VERSION 5.7 ;
  NOWIREEXTENSIONATPIN ON ;
  DIVIDERCHAR "/" ;
  BUSBITCHARS "[]" ;
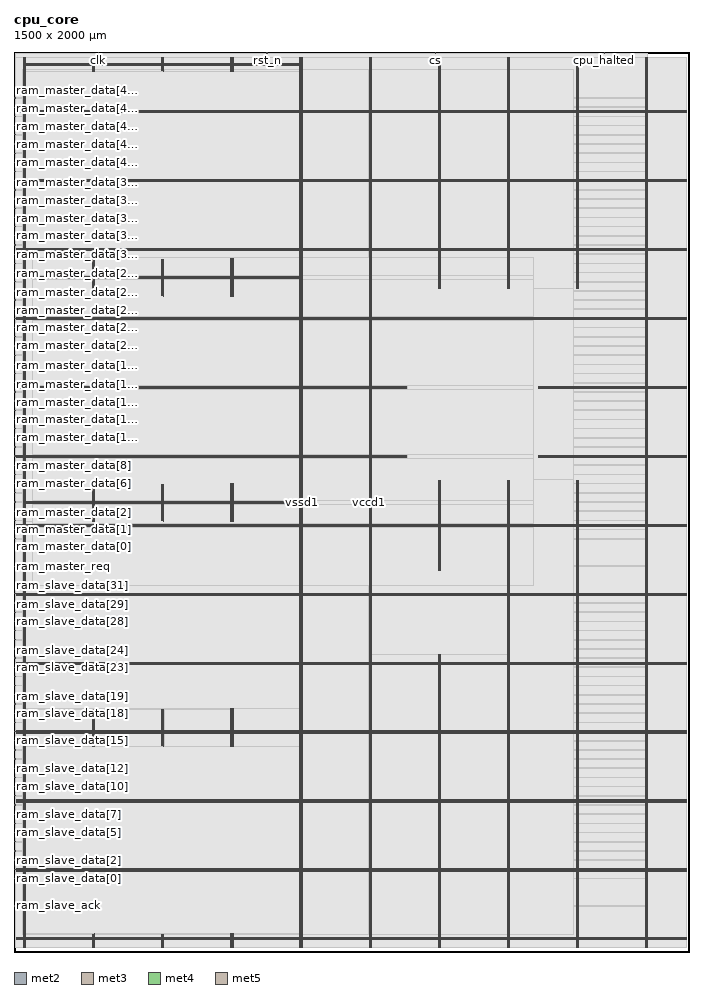
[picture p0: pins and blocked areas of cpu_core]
MACRO cpu_core
  CLASS BLOCK ;
  FOREIGN cpu_core ;
  ORIGIN 0.000 0.000 ;
  SIZE 1500.000 BY 2000.000 ;
  PIN clk
    DIRECTION INPUT ;
    USE SIGNAL ;
    ANTENNAGATEAREA 2.573400 ;
    ANTENNADIFFAREA 0.869400 ;
    PORT
      LAYER met2 ;
        RECT 187.310 1996.000 187.590 2000.000 ;
    END
  END clk
  PIN cpu_halted
    DIRECTION OUTPUT ;
    USE SIGNAL ;
    ANTENNADIFFAREA 0.445500 ;
    PORT
      LAYER met2 ;
        RECT 1312.010 1996.000 1312.290 2000.000 ;
    END
  END cpu_halted
  PIN cs
    DIRECTION INPUT ;
    USE SIGNAL ;
    ANTENNAGATEAREA 0.860700 ;
    ANTENNADIFFAREA 0.434700 ;
    PORT
      LAYER met2 ;
        RECT 937.110 1996.000 937.390 2000.000 ;
    END
  END cs
  PIN ram_master_data[0]
    DIRECTION OUTPUT ;
    USE SIGNAL ;
    ANTENNADIFFAREA 0.445500 ;
    PORT
      LAYER met3 ;
        RECT 0.000 918.040 4.000 918.640 ;
    END
  END ram_master_data[0]
  PIN ram_master_data[10]
    DIRECTION OUTPUT ;
    USE SIGNAL ;
    ANTENNADIFFAREA 0.445500 ;
    PORT
      LAYER met3 ;
        RECT 0.000 1122.040 4.000 1122.640 ;
    END
  END ram_master_data[10]
  PIN ram_master_data[11]
    DIRECTION OUTPUT ;
    USE SIGNAL ;
    ANTENNADIFFAREA 0.445500 ;
    PORT
      LAYER met3 ;
        RECT 0.000 1142.440 4.000 1143.040 ;
    END
  END ram_master_data[11]
  PIN ram_master_data[12]
    DIRECTION OUTPUT ;
    USE SIGNAL ;
    ANTENNADIFFAREA 0.445500 ;
    PORT
      LAYER met3 ;
        RECT 0.000 1162.840 4.000 1163.440 ;
    END
  END ram_master_data[12]
  PIN ram_master_data[13]
    DIRECTION OUTPUT ;
    USE SIGNAL ;
    ANTENNADIFFAREA 0.445500 ;
    PORT
      LAYER met3 ;
        RECT 0.000 1183.240 4.000 1183.840 ;
    END
  END ram_master_data[13]
  PIN ram_master_data[14]
    DIRECTION OUTPUT ;
    USE SIGNAL ;
    ANTENNADIFFAREA 0.445500 ;
    PORT
      LAYER met3 ;
        RECT 0.000 1203.640 4.000 1204.240 ;
    END
  END ram_master_data[14]
  PIN ram_master_data[15]
    DIRECTION OUTPUT ;
    USE SIGNAL ;
    ANTENNADIFFAREA 0.445500 ;
    PORT
      LAYER met3 ;
        RECT 0.000 1224.040 4.000 1224.640 ;
    END
  END ram_master_data[15]
  PIN ram_master_data[16]
    DIRECTION OUTPUT ;
    USE SIGNAL ;
    ANTENNADIFFAREA 0.445500 ;
    PORT
      LAYER met3 ;
        RECT 0.000 1244.440 4.000 1245.040 ;
    END
  END ram_master_data[16]
  PIN ram_master_data[17]
    DIRECTION OUTPUT ;
    USE SIGNAL ;
    ANTENNADIFFAREA 0.445500 ;
    PORT
      LAYER met3 ;
        RECT 0.000 1264.840 4.000 1265.440 ;
    END
  END ram_master_data[17]
  PIN ram_master_data[18]
    DIRECTION OUTPUT ;
    USE SIGNAL ;
    ANTENNADIFFAREA 0.445500 ;
    PORT
      LAYER met3 ;
        RECT 0.000 1285.240 4.000 1285.840 ;
    END
  END ram_master_data[18]
  PIN ram_master_data[19]
    DIRECTION OUTPUT ;
    USE SIGNAL ;
    ANTENNADIFFAREA 0.445500 ;
    PORT
      LAYER met3 ;
        RECT 0.000 1305.640 4.000 1306.240 ;
    END
  END ram_master_data[19]
  PIN ram_master_data[1]
    DIRECTION OUTPUT ;
    USE SIGNAL ;
    ANTENNADIFFAREA 0.445500 ;
    PORT
      LAYER met3 ;
        RECT 0.000 938.440 4.000 939.040 ;
    END
  END ram_master_data[1]
  PIN ram_master_data[20]
    DIRECTION OUTPUT ;
    USE SIGNAL ;
    ANTENNADIFFAREA 0.445500 ;
    PORT
      LAYER met3 ;
        RECT 0.000 1326.040 4.000 1326.640 ;
    END
  END ram_master_data[20]
  PIN ram_master_data[21]
    DIRECTION OUTPUT ;
    USE SIGNAL ;
    ANTENNADIFFAREA 0.445500 ;
    PORT
      LAYER met3 ;
        RECT 0.000 1346.440 4.000 1347.040 ;
    END
  END ram_master_data[21]
  PIN ram_master_data[22]
    DIRECTION OUTPUT ;
    USE SIGNAL ;
    ANTENNADIFFAREA 0.445500 ;
    PORT
      LAYER met3 ;
        RECT 0.000 1366.840 4.000 1367.440 ;
    END
  END ram_master_data[22]
  PIN ram_master_data[23]
    DIRECTION OUTPUT ;
    USE SIGNAL ;
    ANTENNADIFFAREA 0.445500 ;
    PORT
      LAYER met3 ;
        RECT 0.000 1387.240 4.000 1387.840 ;
    END
  END ram_master_data[23]
  PIN ram_master_data[24]
    DIRECTION OUTPUT ;
    USE SIGNAL ;
    ANTENNADIFFAREA 0.445500 ;
    PORT
      LAYER met3 ;
        RECT 0.000 1407.640 4.000 1408.240 ;
    END
  END ram_master_data[24]
  PIN ram_master_data[25]
    DIRECTION OUTPUT ;
    USE SIGNAL ;
    ANTENNADIFFAREA 0.445500 ;
    PORT
      LAYER met3 ;
        RECT 0.000 1428.040 4.000 1428.640 ;
    END
  END ram_master_data[25]
  PIN ram_master_data[26]
    DIRECTION OUTPUT ;
    USE SIGNAL ;
    ANTENNADIFFAREA 0.445500 ;
    PORT
      LAYER met3 ;
        RECT 0.000 1448.440 4.000 1449.040 ;
    END
  END ram_master_data[26]
  PIN ram_master_data[27]
    DIRECTION OUTPUT ;
    USE SIGNAL ;
    ANTENNADIFFAREA 0.445500 ;
    PORT
      LAYER met3 ;
        RECT 0.000 1468.840 4.000 1469.440 ;
    END
  END ram_master_data[27]
  PIN ram_master_data[28]
    DIRECTION OUTPUT ;
    USE SIGNAL ;
    ANTENNADIFFAREA 0.445500 ;
    PORT
      LAYER met3 ;
        RECT 0.000 1489.240 4.000 1489.840 ;
    END
  END ram_master_data[28]
  PIN ram_master_data[29]
    DIRECTION OUTPUT ;
    USE SIGNAL ;
    ANTENNADIFFAREA 0.445500 ;
    PORT
      LAYER met3 ;
        RECT 0.000 1509.640 4.000 1510.240 ;
    END
  END ram_master_data[29]
  PIN ram_master_data[2]
    DIRECTION OUTPUT ;
    USE SIGNAL ;
    ANTENNADIFFAREA 0.445500 ;
    PORT
      LAYER met3 ;
        RECT 0.000 958.840 4.000 959.440 ;
    END
  END ram_master_data[2]
  PIN ram_master_data[30]
    DIRECTION OUTPUT ;
    USE SIGNAL ;
    ANTENNADIFFAREA 0.445500 ;
    PORT
      LAYER met3 ;
        RECT 0.000 1530.040 4.000 1530.640 ;
    END
  END ram_master_data[30]
  PIN ram_master_data[31]
    DIRECTION OUTPUT ;
    USE SIGNAL ;
    ANTENNADIFFAREA 0.445500 ;
    PORT
      LAYER met3 ;
        RECT 0.000 1550.440 4.000 1551.040 ;
    END
  END ram_master_data[31]
  PIN ram_master_data[32]
    DIRECTION OUTPUT ;
    USE SIGNAL ;
    ANTENNADIFFAREA 0.445500 ;
    PORT
      LAYER met3 ;
        RECT 0.000 1570.840 4.000 1571.440 ;
    END
  END ram_master_data[32]
  PIN ram_master_data[33]
    DIRECTION OUTPUT ;
    USE SIGNAL ;
    ANTENNADIFFAREA 0.445500 ;
    PORT
      LAYER met3 ;
        RECT 0.000 1591.240 4.000 1591.840 ;
    END
  END ram_master_data[33]
  PIN ram_master_data[34]
    DIRECTION OUTPUT ;
    USE SIGNAL ;
    ANTENNADIFFAREA 0.445500 ;
    PORT
      LAYER met3 ;
        RECT 0.000 1611.640 4.000 1612.240 ;
    END
  END ram_master_data[34]
  PIN ram_master_data[35]
    DIRECTION OUTPUT ;
    USE SIGNAL ;
    ANTENNADIFFAREA 0.445500 ;
    PORT
      LAYER met3 ;
        RECT 0.000 1632.040 4.000 1632.640 ;
    END
  END ram_master_data[35]
  PIN ram_master_data[36]
    DIRECTION OUTPUT ;
    USE SIGNAL ;
    ANTENNADIFFAREA 0.445500 ;
    PORT
      LAYER met3 ;
        RECT 0.000 1652.440 4.000 1653.040 ;
    END
  END ram_master_data[36]
  PIN ram_master_data[37]
    DIRECTION OUTPUT ;
    USE SIGNAL ;
    ANTENNADIFFAREA 0.445500 ;
    PORT
      LAYER met3 ;
        RECT 0.000 1672.840 4.000 1673.440 ;
    END
  END ram_master_data[37]
  PIN ram_master_data[38]
    DIRECTION OUTPUT ;
    USE SIGNAL ;
    ANTENNADIFFAREA 0.445500 ;
    PORT
      LAYER met3 ;
        RECT 0.000 1693.240 4.000 1693.840 ;
    END
  END ram_master_data[38]
  PIN ram_master_data[39]
    DIRECTION OUTPUT ;
    USE SIGNAL ;
    ANTENNADIFFAREA 0.445500 ;
    PORT
      LAYER met3 ;
        RECT 0.000 1713.640 4.000 1714.240 ;
    END
  END ram_master_data[39]
  PIN ram_master_data[3]
    DIRECTION OUTPUT ;
    USE SIGNAL ;
    ANTENNADIFFAREA 0.445500 ;
    PORT
      LAYER met3 ;
        RECT 0.000 979.240 4.000 979.840 ;
    END
  END ram_master_data[3]
  PIN ram_master_data[40]
    DIRECTION OUTPUT ;
    USE SIGNAL ;
    ANTENNADIFFAREA 0.445500 ;
    PORT
      LAYER met3 ;
        RECT 0.000 1734.040 4.000 1734.640 ;
    END
  END ram_master_data[40]
  PIN ram_master_data[41]
    DIRECTION OUTPUT ;
    USE SIGNAL ;
    ANTENNADIFFAREA 0.445500 ;
    PORT
      LAYER met3 ;
        RECT 0.000 1754.440 4.000 1755.040 ;
    END
  END ram_master_data[41]
  PIN ram_master_data[42]
    DIRECTION OUTPUT ;
    USE SIGNAL ;
    ANTENNADIFFAREA 0.445500 ;
    PORT
      LAYER met3 ;
        RECT 0.000 1774.840 4.000 1775.440 ;
    END
  END ram_master_data[42]
  PIN ram_master_data[43]
    DIRECTION OUTPUT ;
    USE SIGNAL ;
    ANTENNADIFFAREA 0.445500 ;
    PORT
      LAYER met3 ;
        RECT 0.000 1795.240 4.000 1795.840 ;
    END
  END ram_master_data[43]
  PIN ram_master_data[44]
    DIRECTION OUTPUT ;
    USE SIGNAL ;
    ANTENNADIFFAREA 0.445500 ;
    PORT
      LAYER met3 ;
        RECT 0.000 1815.640 4.000 1816.240 ;
    END
  END ram_master_data[44]
  PIN ram_master_data[45]
    DIRECTION OUTPUT ;
    USE SIGNAL ;
    ANTENNADIFFAREA 0.445500 ;
    PORT
      LAYER met3 ;
        RECT 0.000 1836.040 4.000 1836.640 ;
    END
  END ram_master_data[45]
  PIN ram_master_data[46]
    DIRECTION OUTPUT ;
    USE SIGNAL ;
    ANTENNADIFFAREA 0.445500 ;
    PORT
      LAYER met3 ;
        RECT 0.000 1856.440 4.000 1857.040 ;
    END
  END ram_master_data[46]
  PIN ram_master_data[47]
    DIRECTION OUTPUT ;
    USE SIGNAL ;
    ANTENNADIFFAREA 0.445500 ;
    PORT
      LAYER met3 ;
        RECT 0.000 1876.840 4.000 1877.440 ;
    END
  END ram_master_data[47]
  PIN ram_master_data[48]
    DIRECTION OUTPUT ;
    USE SIGNAL ;
    ANTENNADIFFAREA 0.445500 ;
    PORT
      LAYER met3 ;
        RECT 0.000 1897.240 4.000 1897.840 ;
    END
  END ram_master_data[48]
  PIN ram_master_data[4]
    DIRECTION OUTPUT ;
    USE SIGNAL ;
    ANTENNADIFFAREA 0.445500 ;
    PORT
      LAYER met3 ;
        RECT 0.000 999.640 4.000 1000.240 ;
    END
  END ram_master_data[4]
  PIN ram_master_data[5]
    DIRECTION OUTPUT ;
    USE SIGNAL ;
    ANTENNADIFFAREA 0.445500 ;
    PORT
      LAYER met3 ;
        RECT 0.000 1020.040 4.000 1020.640 ;
    END
  END ram_master_data[5]
  PIN ram_master_data[6]
    DIRECTION OUTPUT ;
    USE SIGNAL ;
    ANTENNADIFFAREA 0.445500 ;
    PORT
      LAYER met3 ;
        RECT 0.000 1040.440 4.000 1041.040 ;
    END
  END ram_master_data[6]
  PIN ram_master_data[7]
    DIRECTION OUTPUT ;
    USE SIGNAL ;
    ANTENNADIFFAREA 0.445500 ;
    PORT
      LAYER met3 ;
        RECT 0.000 1060.840 4.000 1061.440 ;
    END
  END ram_master_data[7]
  PIN ram_master_data[8]
    DIRECTION OUTPUT ;
    USE SIGNAL ;
    ANTENNADIFFAREA 0.445500 ;
    PORT
      LAYER met3 ;
        RECT 0.000 1081.240 4.000 1081.840 ;
    END
  END ram_master_data[8]
  PIN ram_master_data[9]
    DIRECTION OUTPUT ;
    USE SIGNAL ;
    ANTENNADIFFAREA 0.445500 ;
    PORT
      LAYER met3 ;
        RECT 0.000 1101.640 4.000 1102.240 ;
    END
  END ram_master_data[9]
  PIN ram_master_req
    DIRECTION OUTPUT ;
    USE SIGNAL ;
    ANTENNADIFFAREA 0.445500 ;
    PORT
      LAYER met3 ;
        RECT 0.000 856.840 4.000 857.440 ;
    END
  END ram_master_req
  PIN ram_slave_ack
    DIRECTION INPUT ;
    USE SIGNAL ;
    ANTENNAGATEAREA 0.682200 ;
    ANTENNADIFFAREA 0.434700 ;
    PORT
      LAYER met3 ;
        RECT 0.000 102.040 4.000 102.640 ;
    END
  END ram_slave_ack
  PIN ram_slave_data[0]
    DIRECTION INPUT ;
    USE SIGNAL ;
    ANTENNAGATEAREA 0.593700 ;
    ANTENNADIFFAREA 0.434700 ;
    PORT
      LAYER met3 ;
        RECT 0.000 163.240 4.000 163.840 ;
    END
  END ram_slave_data[0]
  PIN ram_slave_data[10]
    DIRECTION INPUT ;
    USE SIGNAL ;
    ANTENNAGATEAREA 0.631200 ;
    ANTENNADIFFAREA 0.434700 ;
    PORT
      LAYER met3 ;
        RECT 0.000 367.240 4.000 367.840 ;
    END
  END ram_slave_data[10]
  PIN ram_slave_data[11]
    DIRECTION INPUT ;
    USE SIGNAL ;
    ANTENNAGATEAREA 0.631200 ;
    ANTENNADIFFAREA 0.434700 ;
    PORT
      LAYER met3 ;
        RECT 0.000 387.640 4.000 388.240 ;
    END
  END ram_slave_data[11]
  PIN ram_slave_data[12]
    DIRECTION INPUT ;
    USE SIGNAL ;
    ANTENNAGATEAREA 0.631200 ;
    ANTENNADIFFAREA 0.434700 ;
    PORT
      LAYER met3 ;
        RECT 0.000 408.040 4.000 408.640 ;
    END
  END ram_slave_data[12]
  PIN ram_slave_data[13]
    DIRECTION INPUT ;
    USE SIGNAL ;
    ANTENNAGATEAREA 0.631200 ;
    ANTENNADIFFAREA 0.434700 ;
    PORT
      LAYER met3 ;
        RECT 0.000 428.440 4.000 429.040 ;
    END
  END ram_slave_data[13]
  PIN ram_slave_data[14]
    DIRECTION INPUT ;
    USE SIGNAL ;
    ANTENNAGATEAREA 0.631200 ;
    ANTENNADIFFAREA 0.434700 ;
    PORT
      LAYER met3 ;
        RECT 0.000 448.840 4.000 449.440 ;
    END
  END ram_slave_data[14]
  PIN ram_slave_data[15]
    DIRECTION INPUT ;
    USE SIGNAL ;
    ANTENNAGATEAREA 0.631200 ;
    ANTENNADIFFAREA 0.434700 ;
    PORT
      LAYER met3 ;
        RECT 0.000 469.240 4.000 469.840 ;
    END
  END ram_slave_data[15]
  PIN ram_slave_data[16]
    DIRECTION INPUT ;
    USE SIGNAL ;
    ANTENNAGATEAREA 0.631200 ;
    ANTENNADIFFAREA 0.434700 ;
    PORT
      LAYER met3 ;
        RECT 0.000 489.640 4.000 490.240 ;
    END
  END ram_slave_data[16]
  PIN ram_slave_data[17]
    DIRECTION INPUT ;
    USE SIGNAL ;
    ANTENNAGATEAREA 0.631200 ;
    ANTENNADIFFAREA 0.434700 ;
    PORT
      LAYER met3 ;
        RECT 0.000 510.040 4.000 510.640 ;
    END
  END ram_slave_data[17]
  PIN ram_slave_data[18]
    DIRECTION INPUT ;
    USE SIGNAL ;
    ANTENNAGATEAREA 0.631200 ;
    ANTENNADIFFAREA 0.434700 ;
    PORT
      LAYER met3 ;
        RECT 0.000 530.440 4.000 531.040 ;
    END
  END ram_slave_data[18]
  PIN ram_slave_data[19]
    DIRECTION INPUT ;
    USE SIGNAL ;
    ANTENNAGATEAREA 0.631200 ;
    ANTENNADIFFAREA 0.434700 ;
    PORT
      LAYER met3 ;
        RECT 0.000 550.840 4.000 551.440 ;
    END
  END ram_slave_data[19]
  PIN ram_slave_data[1]
    DIRECTION INPUT ;
    USE SIGNAL ;
    ANTENNAGATEAREA 0.593700 ;
    ANTENNADIFFAREA 0.434700 ;
    PORT
      LAYER met3 ;
        RECT 0.000 183.640 4.000 184.240 ;
    END
  END ram_slave_data[1]
  PIN ram_slave_data[20]
    DIRECTION INPUT ;
    USE SIGNAL ;
    ANTENNAGATEAREA 0.631200 ;
    ANTENNADIFFAREA 0.434700 ;
    PORT
      LAYER met3 ;
        RECT 0.000 571.240 4.000 571.840 ;
    END
  END ram_slave_data[20]
  PIN ram_slave_data[21]
    DIRECTION INPUT ;
    USE SIGNAL ;
    ANTENNAGATEAREA 0.631200 ;
    ANTENNADIFFAREA 0.434700 ;
    PORT
      LAYER met3 ;
        RECT 0.000 591.640 4.000 592.240 ;
    END
  END ram_slave_data[21]
  PIN ram_slave_data[22]
    DIRECTION INPUT ;
    USE SIGNAL ;
    ANTENNAGATEAREA 0.631200 ;
    ANTENNADIFFAREA 0.434700 ;
    PORT
      LAYER met3 ;
        RECT 0.000 612.040 4.000 612.640 ;
    END
  END ram_slave_data[22]
  PIN ram_slave_data[23]
    DIRECTION INPUT ;
    USE SIGNAL ;
    ANTENNAGATEAREA 0.647700 ;
    ANTENNADIFFAREA 0.434700 ;
    PORT
      LAYER met3 ;
        RECT 0.000 632.440 4.000 633.040 ;
    END
  END ram_slave_data[23]
  PIN ram_slave_data[24]
    DIRECTION INPUT ;
    USE SIGNAL ;
    ANTENNAGATEAREA 0.647700 ;
    ANTENNADIFFAREA 0.434700 ;
    PORT
      LAYER met3 ;
        RECT 0.000 652.840 4.000 653.440 ;
    END
  END ram_slave_data[24]
  PIN ram_slave_data[25]
    DIRECTION INPUT ;
    USE SIGNAL ;
    ANTENNAGATEAREA 0.647700 ;
    ANTENNADIFFAREA 0.434700 ;
    PORT
      LAYER met3 ;
        RECT 0.000 673.240 4.000 673.840 ;
    END
  END ram_slave_data[25]
  PIN ram_slave_data[26]
    DIRECTION INPUT ;
    USE SIGNAL ;
    ANTENNAGATEAREA 0.647700 ;
    ANTENNADIFFAREA 0.434700 ;
    PORT
      LAYER met3 ;
        RECT 0.000 693.640 4.000 694.240 ;
    END
  END ram_slave_data[26]
  PIN ram_slave_data[27]
    DIRECTION INPUT ;
    USE SIGNAL ;
    ANTENNAGATEAREA 0.560700 ;
    ANTENNADIFFAREA 0.434700 ;
    PORT
      LAYER met3 ;
        RECT 0.000 714.040 4.000 714.640 ;
    END
  END ram_slave_data[27]
  PIN ram_slave_data[28]
    DIRECTION INPUT ;
    USE SIGNAL ;
    ANTENNAGATEAREA 0.560700 ;
    ANTENNADIFFAREA 0.434700 ;
    PORT
      LAYER met3 ;
        RECT 0.000 734.440 4.000 735.040 ;
    END
  END ram_slave_data[28]
  PIN ram_slave_data[29]
    DIRECTION INPUT ;
    USE SIGNAL ;
    ANTENNAGATEAREA 0.631200 ;
    ANTENNADIFFAREA 0.434700 ;
    PORT
      LAYER met3 ;
        RECT 0.000 754.840 4.000 755.440 ;
    END
  END ram_slave_data[29]
  PIN ram_slave_data[2]
    DIRECTION INPUT ;
    USE SIGNAL ;
    ANTENNAGATEAREA 0.647700 ;
    ANTENNADIFFAREA 0.434700 ;
    PORT
      LAYER met3 ;
        RECT 0.000 204.040 4.000 204.640 ;
    END
  END ram_slave_data[2]
  PIN ram_slave_data[30]
    DIRECTION INPUT ;
    USE SIGNAL ;
    ANTENNAGATEAREA 0.631200 ;
    ANTENNADIFFAREA 0.434700 ;
    PORT
      LAYER met3 ;
        RECT 0.000 775.240 4.000 775.840 ;
    END
  END ram_slave_data[30]
  PIN ram_slave_data[31]
    DIRECTION INPUT ;
    USE SIGNAL ;
    ANTENNAGATEAREA 0.631200 ;
    ANTENNADIFFAREA 0.434700 ;
    PORT
      LAYER met3 ;
        RECT 0.000 795.640 4.000 796.240 ;
    END
  END ram_slave_data[31]
  PIN ram_slave_data[3]
    DIRECTION INPUT ;
    USE SIGNAL ;
    ANTENNAGATEAREA 0.593700 ;
    ANTENNADIFFAREA 0.434700 ;
    PORT
      LAYER met3 ;
        RECT 0.000 224.440 4.000 225.040 ;
    END
  END ram_slave_data[3]
  PIN ram_slave_data[4]
    DIRECTION INPUT ;
    USE SIGNAL ;
    ANTENNAGATEAREA 0.647700 ;
    ANTENNADIFFAREA 0.434700 ;
    PORT
      LAYER met3 ;
        RECT 0.000 244.840 4.000 245.440 ;
    END
  END ram_slave_data[4]
  PIN ram_slave_data[5]
    DIRECTION INPUT ;
    USE SIGNAL ;
    ANTENNAGATEAREA 0.647700 ;
    ANTENNADIFFAREA 0.434700 ;
    PORT
      LAYER met3 ;
        RECT 0.000 265.240 4.000 265.840 ;
    END
  END ram_slave_data[5]
  PIN ram_slave_data[6]
    DIRECTION INPUT ;
    USE SIGNAL ;
    ANTENNAGATEAREA 0.647700 ;
    ANTENNADIFFAREA 0.434700 ;
    PORT
      LAYER met3 ;
        RECT 0.000 285.640 4.000 286.240 ;
    END
  END ram_slave_data[6]
  PIN ram_slave_data[7]
    DIRECTION INPUT ;
    USE SIGNAL ;
    ANTENNAGATEAREA 0.647700 ;
    ANTENNADIFFAREA 0.434700 ;
    PORT
      LAYER met3 ;
        RECT 0.000 306.040 4.000 306.640 ;
    END
  END ram_slave_data[7]
  PIN ram_slave_data[8]
    DIRECTION INPUT ;
    USE SIGNAL ;
    ANTENNAGATEAREA 0.560700 ;
    ANTENNADIFFAREA 0.434700 ;
    PORT
      LAYER met3 ;
        RECT 0.000 326.440 4.000 327.040 ;
    END
  END ram_slave_data[8]
  PIN ram_slave_data[9]
    DIRECTION INPUT ;
    USE SIGNAL ;
    ANTENNAGATEAREA 0.560700 ;
    ANTENNADIFFAREA 0.434700 ;
    PORT
      LAYER met3 ;
        RECT 0.000 346.840 4.000 347.440 ;
    END
  END ram_slave_data[9]
  PIN rst_n
    DIRECTION INPUT ;
    USE SIGNAL ;
    ANTENNAGATEAREA 0.647700 ;
    ANTENNADIFFAREA 0.434700 ;
    PORT
      LAYER met2 ;
        RECT 562.210 1996.000 562.490 2000.000 ;
    END
  END rst_n
  PIN vccd1
    DIRECTION INOUT ;
    USE POWER ;
    PORT
      LAYER met4 ;
        RECT 21.040 10.640 22.640 1988.560 ;
    END
    PORT
      LAYER met4 ;
        RECT 174.640 10.640 176.240 39.400 ;
    END
    PORT
      LAYER met4 ;
        RECT 174.640 457.180 176.240 539.400 ;
    END
    PORT
      LAYER met4 ;
        RECT 174.640 957.180 176.240 1039.400 ;
    END
    PORT
      LAYER met4 ;
        RECT 174.640 1457.180 176.240 1539.400 ;
    END
    PORT
      LAYER met4 ;
        RECT 174.640 1957.180 176.240 1988.560 ;
    END
    PORT
      LAYER met4 ;
        RECT 328.240 10.640 329.840 39.400 ;
    END
    PORT
      LAYER met4 ;
        RECT 328.240 458.100 329.840 539.400 ;
    END
    PORT
      LAYER met4 ;
        RECT 328.240 958.100 329.840 1039.400 ;
    END
    PORT
      LAYER met4 ;
        RECT 328.240 1458.100 329.840 1539.400 ;
    END
    PORT
      LAYER met4 ;
        RECT 328.240 1958.100 329.840 1988.560 ;
    END
    PORT
      LAYER met4 ;
        RECT 481.840 10.640 483.440 40.320 ;
    END
    PORT
      LAYER met4 ;
        RECT 481.840 457.180 483.440 540.320 ;
    END
    PORT
      LAYER met4 ;
        RECT 481.840 957.180 483.440 1040.320 ;
    END
    PORT
      LAYER met4 ;
        RECT 481.840 1457.180 483.440 1540.320 ;
    END
    PORT
      LAYER met4 ;
        RECT 481.840 1957.180 483.440 1988.560 ;
    END
    PORT
      LAYER met4 ;
        RECT 635.440 10.640 637.040 1988.560 ;
    END
    PORT
      LAYER met4 ;
        RECT 789.040 10.640 790.640 1988.560 ;
    END
    PORT
      LAYER met4 ;
        RECT 942.640 10.640 944.240 660.275 ;
    END
    PORT
      LAYER met4 ;
        RECT 942.640 847.125 944.240 1048.715 ;
    END
    PORT
      LAYER met4 ;
        RECT 942.640 1474.925 944.240 1988.560 ;
    END
    PORT
      LAYER met4 ;
        RECT 1096.240 10.640 1097.840 1048.715 ;
    END
    PORT
      LAYER met4 ;
        RECT 1096.240 1474.925 1097.840 1988.560 ;
    END
    PORT
      LAYER met4 ;
        RECT 1249.840 10.640 1251.440 1048.715 ;
    END
    PORT
      LAYER met4 ;
        RECT 1249.840 1474.925 1251.440 1988.560 ;
    END
    PORT
      LAYER met4 ;
        RECT 1403.440 10.640 1405.040 1988.560 ;
    END
    PORT
      LAYER met5 ;
        RECT 5.280 26.730 1494.320 28.330 ;
    END
    PORT
      LAYER met5 ;
        RECT 5.280 179.910 1494.320 181.510 ;
    END
    PORT
      LAYER met5 ;
        RECT 5.280 333.090 1494.320 334.690 ;
    END
    PORT
      LAYER met5 ;
        RECT 5.280 486.270 1494.320 487.870 ;
    END
    PORT
      LAYER met5 ;
        RECT 5.280 639.450 1494.320 641.050 ;
    END
    PORT
      LAYER met5 ;
        RECT 5.280 792.630 1494.320 794.230 ;
    END
    PORT
      LAYER met5 ;
        RECT 5.280 945.810 1494.320 947.410 ;
    END
    PORT
      LAYER met5 ;
        RECT 5.280 1098.990 872.260 1100.590 ;
    END
    PORT
      LAYER met5 ;
        RECT 5.280 1252.170 872.260 1253.770 ;
    END
    PORT
      LAYER met5 ;
        RECT 5.280 1405.350 1494.320 1406.950 ;
    END
    PORT
      LAYER met5 ;
        RECT 5.280 1558.530 1494.320 1560.130 ;
    END
    PORT
      LAYER met5 ;
        RECT 5.280 1711.710 1494.320 1713.310 ;
    END
    PORT
      LAYER met5 ;
        RECT 5.280 1864.890 1494.320 1866.490 ;
    END
    PORT
      LAYER met5 ;
        RECT 1165.700 1098.990 1494.320 1100.590 ;
    END
    PORT
      LAYER met5 ;
        RECT 1165.700 1252.170 1494.320 1253.770 ;
    END
    PORT
      LAYER met5 ;
        RECT 21.040 997.100 640.340 998.700 ;
    END
    PORT
      LAYER met5 ;
        RECT 21.040 1496.900 640.340 1498.500 ;
    END
    PORT
      LAYER met5 ;
        RECT 21.040 1969.500 640.340 1971.100 ;
    END
  END vccd1
  PIN vssd1
    DIRECTION INOUT ;
    USE GROUND ;
    PORT
      LAYER met4 ;
        RECT 24.340 10.640 25.940 1988.560 ;
    END
    PORT
      LAYER met4 ;
        RECT 177.940 10.640 179.540 40.320 ;
    END
    PORT
      LAYER met4 ;
        RECT 177.940 457.180 179.540 540.320 ;
    END
    PORT
      LAYER met4 ;
        RECT 177.940 957.180 179.540 1040.320 ;
    END
    PORT
      LAYER met4 ;
        RECT 177.940 1457.180 179.540 1540.320 ;
    END
    PORT
      LAYER met4 ;
        RECT 177.940 1957.180 179.540 1988.560 ;
    END
    PORT
      LAYER met4 ;
        RECT 331.540 10.640 333.140 39.400 ;
    END
    PORT
      LAYER met4 ;
        RECT 331.540 457.180 333.140 539.400 ;
    END
    PORT
      LAYER met4 ;
        RECT 331.540 957.180 333.140 1039.400 ;
    END
    PORT
      LAYER met4 ;
        RECT 331.540 1457.180 333.140 1539.400 ;
    END
    PORT
      LAYER met4 ;
        RECT 331.540 1957.180 333.140 1988.560 ;
    END
    PORT
      LAYER met4 ;
        RECT 485.140 10.640 486.740 40.320 ;
    END
    PORT
      LAYER met4 ;
        RECT 485.140 457.180 486.740 540.320 ;
    END
    PORT
      LAYER met4 ;
        RECT 485.140 957.180 486.740 1040.320 ;
    END
    PORT
      LAYER met4 ;
        RECT 485.140 1457.180 486.740 1540.320 ;
    END
    PORT
      LAYER met4 ;
        RECT 485.140 1957.180 486.740 1988.560 ;
    END
    PORT
      LAYER met4 ;
        RECT 638.740 10.640 640.340 1988.560 ;
    END
    PORT
      LAYER met4 ;
        RECT 792.340 10.640 793.940 1988.560 ;
    END
    PORT
      LAYER met4 ;
        RECT 945.940 10.640 947.540 660.275 ;
    END
    PORT
      LAYER met4 ;
        RECT 945.940 847.125 947.540 1048.715 ;
    END
    PORT
      LAYER met4 ;
        RECT 945.940 1474.925 947.540 1988.560 ;
    END
    PORT
      LAYER met4 ;
        RECT 1099.540 10.640 1101.140 1048.715 ;
    END
    PORT
      LAYER met4 ;
        RECT 1099.540 1474.925 1101.140 1988.560 ;
    END
    PORT
      LAYER met4 ;
        RECT 1253.140 10.640 1254.740 1048.715 ;
    END
    PORT
      LAYER met4 ;
        RECT 1253.140 1474.925 1254.740 1988.560 ;
    END
    PORT
      LAYER met4 ;
        RECT 1406.740 10.640 1408.340 1988.560 ;
    END
    PORT
      LAYER met5 ;
        RECT 5.280 30.030 1494.320 31.630 ;
    END
    PORT
      LAYER met5 ;
        RECT 5.280 183.210 1494.320 184.810 ;
    END
    PORT
      LAYER met5 ;
        RECT 5.280 336.390 1494.320 337.990 ;
    END
    PORT
      LAYER met5 ;
        RECT 5.280 489.570 1494.320 491.170 ;
    END
    PORT
      LAYER met5 ;
        RECT 5.280 642.750 1494.320 644.350 ;
    END
    PORT
      LAYER met5 ;
        RECT 5.280 795.930 1494.320 797.530 ;
    END
    PORT
      LAYER met5 ;
        RECT 5.280 949.110 1494.320 950.710 ;
    END
    PORT
      LAYER met5 ;
        RECT 5.280 1102.290 872.260 1103.890 ;
    END
    PORT
      LAYER met5 ;
        RECT 5.280 1255.470 872.260 1257.070 ;
    END
    PORT
      LAYER met5 ;
        RECT 5.280 1408.650 1494.320 1410.250 ;
    END
    PORT
      LAYER met5 ;
        RECT 5.280 1561.830 1494.320 1563.430 ;
    END
    PORT
      LAYER met5 ;
        RECT 5.280 1715.010 1494.320 1716.610 ;
    END
    PORT
      LAYER met5 ;
        RECT 5.280 1868.190 1494.320 1869.790 ;
    END
    PORT
      LAYER met5 ;
        RECT 1165.700 1102.290 1494.320 1103.890 ;
    END
    PORT
      LAYER met5 ;
        RECT 1165.700 1255.470 1494.320 1257.070 ;
    END
    PORT
      LAYER met5 ;
        RECT 21.040 1000.500 640.340 1002.100 ;
    END
    PORT
      LAYER met5 ;
        RECT 21.040 1500.300 640.340 1501.900 ;
    END
    PORT
      LAYER met5 ;
        RECT 21.040 1972.900 640.340 1974.500 ;
    END
  END vssd1
  OBS
      LAYER nwell ;
        RECT 5.330 10.795 1494.270 1988.510 ;
      LAYER li1 ;
        RECT 5.520 10.795 1494.080 1988.405 ;
      LAYER met1 ;
        RECT 4.210 10.640 1494.080 1988.560 ;
      LAYER met2 ;
        RECT 4.230 1995.720 187.030 1996.000 ;
        RECT 187.870 1995.720 561.930 1996.000 ;
        RECT 562.770 1995.720 936.830 1996.000 ;
        RECT 937.670 1995.720 1311.730 1996.000 ;
        RECT 1312.570 1995.720 1408.310 1996.000 ;
        RECT 4.230 10.695 1408.310 1995.720 ;
      LAYER met3 ;
        RECT 3.990 1898.240 1408.330 1988.485 ;
        RECT 4.400 1896.840 1408.330 1898.240 ;
        RECT 3.990 1877.840 1408.330 1896.840 ;
        RECT 4.400 1876.440 1408.330 1877.840 ;
        RECT 3.990 1857.440 1408.330 1876.440 ;
        RECT 4.400 1856.040 1408.330 1857.440 ;
        RECT 3.990 1837.040 1408.330 1856.040 ;
        RECT 4.400 1835.640 1408.330 1837.040 ;
        RECT 3.990 1816.640 1408.330 1835.640 ;
        RECT 4.400 1815.240 1408.330 1816.640 ;
        RECT 3.990 1796.240 1408.330 1815.240 ;
        RECT 4.400 1794.840 1408.330 1796.240 ;
        RECT 3.990 1775.840 1408.330 1794.840 ;
        RECT 4.400 1774.440 1408.330 1775.840 ;
        RECT 3.990 1755.440 1408.330 1774.440 ;
        RECT 4.400 1754.040 1408.330 1755.440 ;
        RECT 3.990 1735.040 1408.330 1754.040 ;
        RECT 4.400 1733.640 1408.330 1735.040 ;
        RECT 3.990 1714.640 1408.330 1733.640 ;
        RECT 4.400 1713.240 1408.330 1714.640 ;
        RECT 3.990 1694.240 1408.330 1713.240 ;
        RECT 4.400 1692.840 1408.330 1694.240 ;
        RECT 3.990 1673.840 1408.330 1692.840 ;
        RECT 4.400 1672.440 1408.330 1673.840 ;
        RECT 3.990 1653.440 1408.330 1672.440 ;
        RECT 4.400 1652.040 1408.330 1653.440 ;
        RECT 3.990 1633.040 1408.330 1652.040 ;
        RECT 4.400 1631.640 1408.330 1633.040 ;
        RECT 3.990 1612.640 1408.330 1631.640 ;
        RECT 4.400 1611.240 1408.330 1612.640 ;
        RECT 3.990 1592.240 1408.330 1611.240 ;
        RECT 4.400 1590.840 1408.330 1592.240 ;
        RECT 3.990 1571.840 1408.330 1590.840 ;
        RECT 4.400 1570.440 1408.330 1571.840 ;
        RECT 3.990 1551.440 1408.330 1570.440 ;
        RECT 4.400 1550.040 1408.330 1551.440 ;
        RECT 3.990 1531.040 1408.330 1550.040 ;
        RECT 4.400 1529.640 1408.330 1531.040 ;
        RECT 3.990 1510.640 1408.330 1529.640 ;
        RECT 4.400 1509.240 1408.330 1510.640 ;
        RECT 3.990 1490.240 1408.330 1509.240 ;
        RECT 4.400 1488.840 1408.330 1490.240 ;
        RECT 3.990 1469.840 1408.330 1488.840 ;
        RECT 4.400 1468.440 1408.330 1469.840 ;
        RECT 3.990 1449.440 1408.330 1468.440 ;
        RECT 4.400 1448.040 1408.330 1449.440 ;
        RECT 3.990 1429.040 1408.330 1448.040 ;
        RECT 4.400 1427.640 1408.330 1429.040 ;
        RECT 3.990 1408.640 1408.330 1427.640 ;
        RECT 4.400 1407.240 1408.330 1408.640 ;
        RECT 3.990 1388.240 1408.330 1407.240 ;
        RECT 4.400 1386.840 1408.330 1388.240 ;
        RECT 3.990 1367.840 1408.330 1386.840 ;
        RECT 4.400 1366.440 1408.330 1367.840 ;
        RECT 3.990 1347.440 1408.330 1366.440 ;
        RECT 4.400 1346.040 1408.330 1347.440 ;
        RECT 3.990 1327.040 1408.330 1346.040 ;
        RECT 4.400 1325.640 1408.330 1327.040 ;
        RECT 3.990 1306.640 1408.330 1325.640 ;
        RECT 4.400 1305.240 1408.330 1306.640 ;
        RECT 3.990 1286.240 1408.330 1305.240 ;
        RECT 4.400 1284.840 1408.330 1286.240 ;
        RECT 3.990 1265.840 1408.330 1284.840 ;
        RECT 4.400 1264.440 1408.330 1265.840 ;
        RECT 3.990 1245.440 1408.330 1264.440 ;
        RECT 4.400 1244.040 1408.330 1245.440 ;
        RECT 3.990 1225.040 1408.330 1244.040 ;
        RECT 4.400 1223.640 1408.330 1225.040 ;
        RECT 3.990 1204.640 1408.330 1223.640 ;
        RECT 4.400 1203.240 1408.330 1204.640 ;
        RECT 3.990 1184.240 1408.330 1203.240 ;
        RECT 4.400 1182.840 1408.330 1184.240 ;
        RECT 3.990 1163.840 1408.330 1182.840 ;
        RECT 4.400 1162.440 1408.330 1163.840 ;
        RECT 3.990 1143.440 1408.330 1162.440 ;
        RECT 4.400 1142.040 1408.330 1143.440 ;
        RECT 3.990 1123.040 1408.330 1142.040 ;
        RECT 4.400 1121.640 1408.330 1123.040 ;
        RECT 3.990 1102.640 1408.330 1121.640 ;
        RECT 4.400 1101.240 1408.330 1102.640 ;
        RECT 3.990 1082.240 1408.330 1101.240 ;
        RECT 4.400 1080.840 1408.330 1082.240 ;
        RECT 3.990 1061.840 1408.330 1080.840 ;
        RECT 4.400 1060.440 1408.330 1061.840 ;
        RECT 3.990 1041.440 1408.330 1060.440 ;
        RECT 4.400 1040.040 1408.330 1041.440 ;
        RECT 3.990 1021.040 1408.330 1040.040 ;
        RECT 4.400 1019.640 1408.330 1021.040 ;
        RECT 3.990 1000.640 1408.330 1019.640 ;
        RECT 4.400 999.240 1408.330 1000.640 ;
        RECT 3.990 980.240 1408.330 999.240 ;
        RECT 4.400 978.840 1408.330 980.240 ;
        RECT 3.990 959.840 1408.330 978.840 ;
        RECT 4.400 958.440 1408.330 959.840 ;
        RECT 3.990 939.440 1408.330 958.440 ;
        RECT 4.400 938.040 1408.330 939.440 ;
        RECT 3.990 919.040 1408.330 938.040 ;
        RECT 4.400 917.640 1408.330 919.040 ;
        RECT 3.990 857.840 1408.330 917.640 ;
        RECT 4.400 856.440 1408.330 857.840 ;
        RECT 3.990 796.640 1408.330 856.440 ;
        RECT 4.400 795.240 1408.330 796.640 ;
        RECT 3.990 776.240 1408.330 795.240 ;
        RECT 4.400 774.840 1408.330 776.240 ;
        RECT 3.990 755.840 1408.330 774.840 ;
        RECT 4.400 754.440 1408.330 755.840 ;
        RECT 3.990 735.440 1408.330 754.440 ;
        RECT 4.400 734.040 1408.330 735.440 ;
        RECT 3.990 715.040 1408.330 734.040 ;
        RECT 4.400 713.640 1408.330 715.040 ;
        RECT 3.990 694.640 1408.330 713.640 ;
        RECT 4.400 693.240 1408.330 694.640 ;
        RECT 3.990 674.240 1408.330 693.240 ;
        RECT 4.400 672.840 1408.330 674.240 ;
        RECT 3.990 653.840 1408.330 672.840 ;
        RECT 4.400 652.440 1408.330 653.840 ;
        RECT 3.990 633.440 1408.330 652.440 ;
        RECT 4.400 632.040 1408.330 633.440 ;
        RECT 3.990 613.040 1408.330 632.040 ;
        RECT 4.400 611.640 1408.330 613.040 ;
        RECT 3.990 592.640 1408.330 611.640 ;
        RECT 4.400 591.240 1408.330 592.640 ;
        RECT 3.990 572.240 1408.330 591.240 ;
        RECT 4.400 570.840 1408.330 572.240 ;
        RECT 3.990 551.840 1408.330 570.840 ;
        RECT 4.400 550.440 1408.330 551.840 ;
        RECT 3.990 531.440 1408.330 550.440 ;
        RECT 4.400 530.040 1408.330 531.440 ;
        RECT 3.990 511.040 1408.330 530.040 ;
        RECT 4.400 509.640 1408.330 511.040 ;
        RECT 3.990 490.640 1408.330 509.640 ;
        RECT 4.400 489.240 1408.330 490.640 ;
        RECT 3.990 470.240 1408.330 489.240 ;
        RECT 4.400 468.840 1408.330 470.240 ;
        RECT 3.990 449.840 1408.330 468.840 ;
        RECT 4.400 448.440 1408.330 449.840 ;
        RECT 3.990 429.440 1408.330 448.440 ;
        RECT 4.400 428.040 1408.330 429.440 ;
        RECT 3.990 409.040 1408.330 428.040 ;
        RECT 4.400 407.640 1408.330 409.040 ;
        RECT 3.990 388.640 1408.330 407.640 ;
        RECT 4.400 387.240 1408.330 388.640 ;
        RECT 3.990 368.240 1408.330 387.240 ;
        RECT 4.400 366.840 1408.330 368.240 ;
        RECT 3.990 347.840 1408.330 366.840 ;
        RECT 4.400 346.440 1408.330 347.840 ;
        RECT 3.990 327.440 1408.330 346.440 ;
        RECT 4.400 326.040 1408.330 327.440 ;
        RECT 3.990 307.040 1408.330 326.040 ;
        RECT 4.400 305.640 1408.330 307.040 ;
        RECT 3.990 286.640 1408.330 305.640 ;
        RECT 4.400 285.240 1408.330 286.640 ;
        RECT 3.990 266.240 1408.330 285.240 ;
        RECT 4.400 264.840 1408.330 266.240 ;
        RECT 3.990 245.840 1408.330 264.840 ;
        RECT 4.400 244.440 1408.330 245.840 ;
        RECT 3.990 225.440 1408.330 244.440 ;
        RECT 4.400 224.040 1408.330 225.440 ;
        RECT 3.990 205.040 1408.330 224.040 ;
        RECT 4.400 203.640 1408.330 205.040 ;
        RECT 3.990 184.640 1408.330 203.640 ;
        RECT 4.400 183.240 1408.330 184.640 ;
        RECT 3.990 164.240 1408.330 183.240 ;
        RECT 4.400 162.840 1408.330 164.240 ;
        RECT 3.990 103.040 1408.330 162.840 ;
        RECT 4.400 101.640 1408.330 103.040 ;
        RECT 3.990 10.715 1408.330 101.640 ;
      LAYER met4 ;
        RECT 19.615 38.935 20.640 1960.265 ;
        RECT 23.040 38.935 23.940 1960.265 ;
        RECT 26.340 1956.780 174.240 1960.265 ;
        RECT 176.640 1956.780 177.540 1960.265 ;
        RECT 179.940 1957.700 327.840 1960.265 ;
        RECT 330.240 1957.700 331.140 1960.265 ;
        RECT 179.940 1956.780 331.140 1957.700 ;
        RECT 333.540 1956.780 481.440 1960.265 ;
        RECT 483.840 1956.780 484.740 1960.265 ;
        RECT 487.140 1956.780 635.040 1960.265 ;
        RECT 26.340 1540.720 635.040 1956.780 ;
        RECT 26.340 1539.800 177.540 1540.720 ;
        RECT 26.340 1456.780 174.240 1539.800 ;
        RECT 176.640 1456.780 177.540 1539.800 ;
        RECT 179.940 1539.800 481.440 1540.720 ;
        RECT 179.940 1457.700 327.840 1539.800 ;
        RECT 330.240 1457.700 331.140 1539.800 ;
        RECT 179.940 1456.780 331.140 1457.700 ;
        RECT 333.540 1456.780 481.440 1539.800 ;
        RECT 483.840 1456.780 484.740 1540.720 ;
        RECT 487.140 1456.780 635.040 1540.720 ;
        RECT 26.340 1040.720 635.040 1456.780 ;
        RECT 26.340 1039.800 177.540 1040.720 ;
        RECT 26.340 956.780 174.240 1039.800 ;
        RECT 176.640 956.780 177.540 1039.800 ;
        RECT 179.940 1039.800 481.440 1040.720 ;
        RECT 179.940 957.700 327.840 1039.800 ;
        RECT 330.240 957.700 331.140 1039.800 ;
        RECT 179.940 956.780 331.140 957.700 ;
        RECT 333.540 956.780 481.440 1039.800 ;
        RECT 483.840 956.780 484.740 1040.720 ;
        RECT 487.140 956.780 635.040 1040.720 ;
        RECT 26.340 540.720 635.040 956.780 ;
        RECT 26.340 539.800 177.540 540.720 ;
        RECT 26.340 456.780 174.240 539.800 ;
        RECT 176.640 456.780 177.540 539.800 ;
        RECT 179.940 539.800 481.440 540.720 ;
        RECT 179.940 457.700 327.840 539.800 ;
        RECT 330.240 457.700 331.140 539.800 ;
        RECT 179.940 456.780 331.140 457.700 ;
        RECT 333.540 456.780 481.440 539.800 ;
        RECT 483.840 456.780 484.740 540.720 ;
        RECT 487.140 456.780 635.040 540.720 ;
        RECT 26.340 40.720 635.040 456.780 ;
        RECT 26.340 39.800 177.540 40.720 ;
        RECT 26.340 38.935 174.240 39.800 ;
        RECT 176.640 38.935 177.540 39.800 ;
        RECT 179.940 39.800 481.440 40.720 ;
        RECT 179.940 38.935 327.840 39.800 ;
        RECT 330.240 38.935 331.140 39.800 ;
        RECT 333.540 38.935 481.440 39.800 ;
        RECT 483.840 38.935 484.740 40.720 ;
        RECT 487.140 38.935 635.040 40.720 ;
        RECT 637.440 38.935 638.340 1960.265 ;
        RECT 640.740 38.935 788.640 1960.265 ;
        RECT 791.040 38.935 791.940 1960.265 ;
        RECT 794.340 1474.525 942.240 1960.265 ;
        RECT 944.640 1474.525 945.540 1960.265 ;
        RECT 947.940 1474.525 1095.840 1960.265 ;
        RECT 1098.240 1474.525 1099.140 1960.265 ;
        RECT 1101.540 1474.525 1243.625 1960.265 ;
        RECT 794.340 1049.115 1243.625 1474.525 ;
        RECT 794.340 846.725 942.240 1049.115 ;
        RECT 944.640 846.725 945.540 1049.115 ;
        RECT 947.940 846.725 1095.840 1049.115 ;
        RECT 794.340 660.675 1095.840 846.725 ;
        RECT 794.340 38.935 942.240 660.675 ;
        RECT 944.640 38.935 945.540 660.675 ;
        RECT 947.940 38.935 1095.840 660.675 ;
        RECT 1098.240 38.935 1099.140 1049.115 ;
        RECT 1101.540 38.935 1243.625 1049.115 ;
      LAYER met5 ;
        RECT 40.140 1503.500 1154.100 1542.700 ;
        RECT 641.940 1495.300 1154.100 1503.500 ;
        RECT 40.140 1411.850 1154.100 1495.300 ;
        RECT 40.140 1258.670 1154.100 1403.750 ;
        RECT 873.860 1250.570 1154.100 1258.670 ;
        RECT 40.140 1105.490 1154.100 1250.570 ;
        RECT 873.860 1097.390 1154.100 1105.490 ;
        RECT 40.140 1003.700 1154.100 1097.390 ;
        RECT 641.940 995.500 1154.100 1003.700 ;
        RECT 40.140 952.310 1154.100 995.500 ;
        RECT 40.140 814.100 1154.100 944.210 ;
  END
END cpu_core
END LIBRARY

